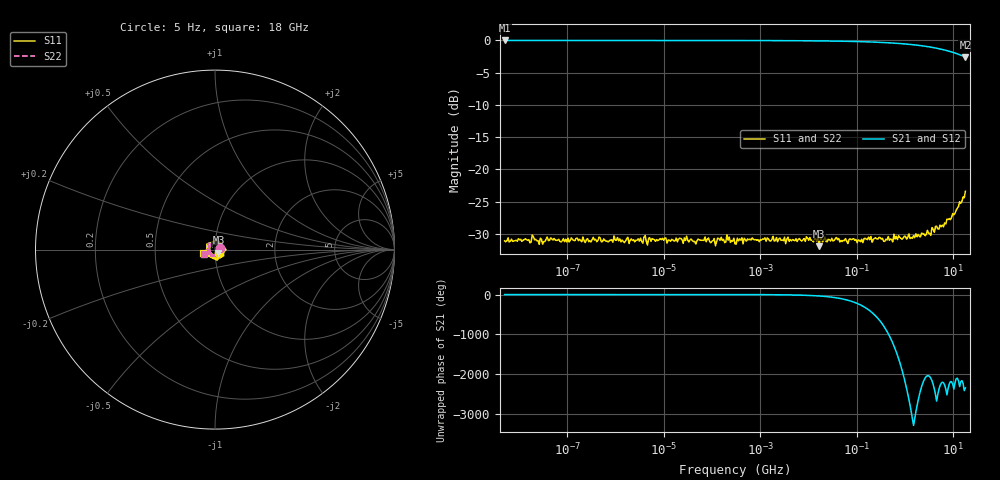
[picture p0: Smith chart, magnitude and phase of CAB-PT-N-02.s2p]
! CAL-ELEKTRA — DATOS SINTÉTICOS DE EJEMPLO: no son una medida real.
! Cable simulado CAB-PT-N-02: 1.5 m, 5 Hz – 18 GHz
# HZ S RI R 50
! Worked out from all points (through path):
!   401 points, 5 Hz to 18 GHz, reference 50 ohm
!   highest |S21| = 0.00 dB at 5 Hz (marker M1); lowest = -2.6 dB at 18 GHz (marker M2)
!   lowest |S11| = -31.9 dB at 16.64 MHz (marker M3), VSWR 1.05, Z = 51.9 - j1.75 ohm
!   |S11| at or under -10 dB: start of sweep to end of sweep
!   |S22| runs from -31.9 to -23.4 dB; largest |S21 - S12| = 0
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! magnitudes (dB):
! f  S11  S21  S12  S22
! 5 Hz  -31.1  0.0  0.0  -31.1
! 15.87 Hz  -30.9  0.0  0.0  -30.9
! 20.9 Hz  -30.9  0.0  0.0  -30.9
! 29.07 Hz  -30.9  0.0  0.0  -30.9
! 42.73 Hz  -31.0  0.0  0.0  -31.0
! 199.4 Hz  -31.2  0.0  0.0  -31.2
! 7.949 kHz  -30.9  0.0  0.0  -30.9
! 33.23 kHz  -31.3  0.0  0.0  -31.3
! 43.75 kHz  -31.2  0.0  0.0  -31.2
! 75.83 kHz  -31.2  0.0  0.0  -31.2
! 105.5 kHz  -31.0  0.0  0.0  -31.0
! 227.9 kHz  -30.5  0.0  0.0  -30.5
! 300 kHz  -31.5  0.0  0.0  -31.5
! 11.96 MHz  -31.0  -0.1  -0.1  -31.0
! 16.64 MHz  -31.9  -0.1  -0.1  -31.9
! 477 MHz  -31.0  -0.4  -0.4  -31.0
! 1.433 GHz  -30.7  -0.7  -0.7  -30.7
! 3.096 GHz  -29.9  -1.0  -1.0  -29.9
! 4.076 GHz  -29.8  -1.1  -1.1  -29.8
! 5.67 GHz  -28.9  -1.4  -1.4  -28.9
! 9.828 GHz  -26.8  -1.8  -1.8  -26.8
! 18 GHz  -23.4  -2.6  -2.6  -23.4
